VERSION 5.7 ;
BUSBITCHARS "[]" ;
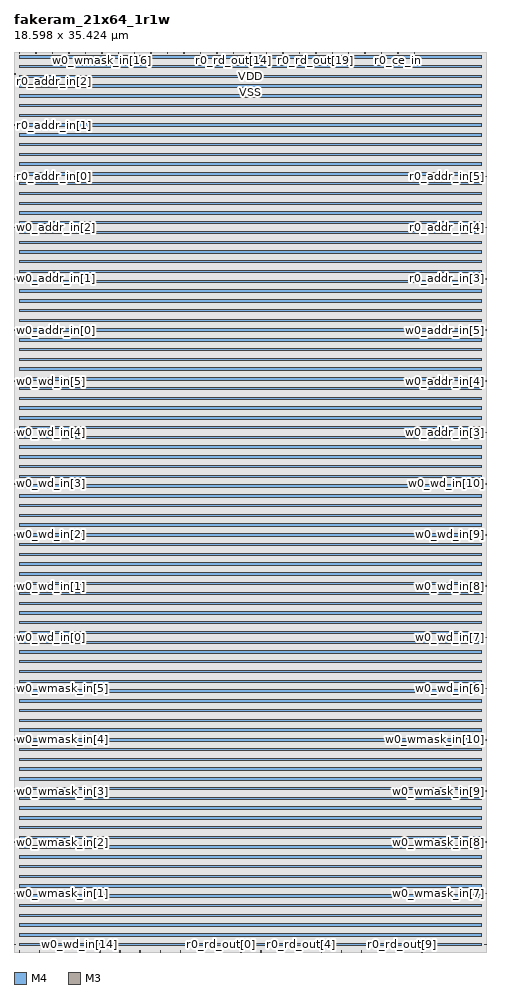
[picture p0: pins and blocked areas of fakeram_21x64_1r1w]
MACRO fakeram_21x64_1r1w
  FOREIGN fakeram_21x64_1r1w 0 0 ;
  SYMMETRY X Y R90 ;
  SIZE 18.598 BY 35.424 ;
  CLASS BLOCK ;
  PIN w0_wmask_in[0]
    DIRECTION INPUT ;
    USE SIGNAL ;
    SHAPE ABUTMENT ;
    PORT
      LAYER M4 ;
      RECT 0.000 0.276 0.072 0.300 ;
    END
  END w0_wmask_in[0]
  PIN w0_wmask_in[1]
    DIRECTION INPUT ;
    USE SIGNAL ;
    SHAPE ABUTMENT ;
    PORT
      LAYER M4 ;
      RECT 0.000 2.292 0.072 2.316 ;
    END
  END w0_wmask_in[1]
  PIN w0_wmask_in[2]
    DIRECTION INPUT ;
    USE SIGNAL ;
    SHAPE ABUTMENT ;
    PORT
      LAYER M4 ;
      RECT 0.000 4.308 0.072 4.332 ;
    END
  END w0_wmask_in[2]
  PIN w0_wmask_in[3]
    DIRECTION INPUT ;
    USE SIGNAL ;
    SHAPE ABUTMENT ;
    PORT
      LAYER M4 ;
      RECT 0.000 6.324 0.072 6.348 ;
    END
  END w0_wmask_in[3]
  PIN w0_wmask_in[4]
    DIRECTION INPUT ;
    USE SIGNAL ;
    SHAPE ABUTMENT ;
    PORT
      LAYER M4 ;
      RECT 0.000 8.340 0.072 8.364 ;
    END
  END w0_wmask_in[4]
  PIN w0_wmask_in[5]
    DIRECTION INPUT ;
    USE SIGNAL ;
    SHAPE ABUTMENT ;
    PORT
      LAYER M4 ;
      RECT 0.000 10.356 0.072 10.380 ;
    END
  END w0_wmask_in[5]
  PIN w0_wmask_in[6]
    DIRECTION INPUT ;
    USE SIGNAL ;
    SHAPE ABUTMENT ;
    PORT
      LAYER M4 ;
      RECT 18.526 0.276 18.598 0.300 ;
    END
  END w0_wmask_in[6]
  PIN w0_wmask_in[7]
    DIRECTION INPUT ;
    USE SIGNAL ;
    SHAPE ABUTMENT ;
    PORT
      LAYER M4 ;
      RECT 18.526 2.292 18.598 2.316 ;
    END
  END w0_wmask_in[7]
  PIN w0_wmask_in[8]
    DIRECTION INPUT ;
    USE SIGNAL ;
    SHAPE ABUTMENT ;
    PORT
      LAYER M4 ;
      RECT 18.526 4.308 18.598 4.332 ;
    END
  END w0_wmask_in[8]
  PIN w0_wmask_in[9]
    DIRECTION INPUT ;
    USE SIGNAL ;
    SHAPE ABUTMENT ;
    PORT
      LAYER M4 ;
      RECT 18.526 6.324 18.598 6.348 ;
    END
  END w0_wmask_in[9]
  PIN w0_wmask_in[10]
    DIRECTION INPUT ;
    USE SIGNAL ;
    SHAPE ABUTMENT ;
    PORT
      LAYER M4 ;
      RECT 18.526 8.340 18.598 8.364 ;
    END
  END w0_wmask_in[10]
  PIN w0_wmask_in[11]
    DIRECTION INPUT ;
    USE SIGNAL ;
    SHAPE ABUTMENT ;
    PORT
      LAYER M3 ;
      RECT 0.207 35.370 0.225 35.424 ;
    END
  END w0_wmask_in[11]
  PIN w0_wmask_in[12]
    DIRECTION INPUT ;
    USE SIGNAL ;
    SHAPE ABUTMENT ;
    PORT
      LAYER M3 ;
      RECT 0.855 35.370 0.873 35.424 ;
    END
  END w0_wmask_in[12]
  PIN w0_wmask_in[13]
    DIRECTION INPUT ;
    USE SIGNAL ;
    SHAPE ABUTMENT ;
    PORT
      LAYER M3 ;
      RECT 1.503 35.370 1.521 35.424 ;
    END
  END w0_wmask_in[13]
  PIN w0_wmask_in[14]
    DIRECTION INPUT ;
    USE SIGNAL ;
    SHAPE ABUTMENT ;
    PORT
      LAYER M3 ;
      RECT 2.151 35.370 2.169 35.424 ;
    END
  END w0_wmask_in[14]
  PIN w0_wmask_in[15]
    DIRECTION INPUT ;
    USE SIGNAL ;
    SHAPE ABUTMENT ;
    PORT
      LAYER M3 ;
      RECT 2.799 35.370 2.817 35.424 ;
    END
  END w0_wmask_in[15]
  PIN w0_wmask_in[16]
    DIRECTION INPUT ;
    USE SIGNAL ;
    SHAPE ABUTMENT ;
    PORT
      LAYER M3 ;
      RECT 3.447 35.370 3.465 35.424 ;
    END
  END w0_wmask_in[16]
  PIN w0_wmask_in[17]
    DIRECTION INPUT ;
    USE SIGNAL ;
    SHAPE ABUTMENT ;
    PORT
      LAYER M3 ;
      RECT 4.095 35.370 4.113 35.424 ;
    END
  END w0_wmask_in[17]
  PIN w0_wmask_in[18]
    DIRECTION INPUT ;
    USE SIGNAL ;
    SHAPE ABUTMENT ;
    PORT
      LAYER M3 ;
      RECT 4.743 35.370 4.761 35.424 ;
    END
  END w0_wmask_in[18]
  PIN w0_wmask_in[19]
    DIRECTION INPUT ;
    USE SIGNAL ;
    SHAPE ABUTMENT ;
    PORT
      LAYER M3 ;
      RECT 5.391 35.370 5.409 35.424 ;
    END
  END w0_wmask_in[19]
  PIN w0_wmask_in[20]
    DIRECTION INPUT ;
    USE SIGNAL ;
    SHAPE ABUTMENT ;
    PORT
      LAYER M3 ;
      RECT 6.039 35.370 6.057 35.424 ;
    END
  END w0_wmask_in[20]
  PIN w0_wd_in[0]
    DIRECTION INPUT ;
    USE SIGNAL ;
    SHAPE ABUTMENT ;
    PORT
      LAYER M4 ;
      RECT 0.000 12.372 0.072 12.396 ;
    END
  END w0_wd_in[0]
  PIN w0_wd_in[1]
    DIRECTION INPUT ;
    USE SIGNAL ;
    SHAPE ABUTMENT ;
    PORT
      LAYER M4 ;
      RECT 0.000 14.388 0.072 14.412 ;
    END
  END w0_wd_in[1]
  PIN w0_wd_in[2]
    DIRECTION INPUT ;
    USE SIGNAL ;
    SHAPE ABUTMENT ;
    PORT
      LAYER M4 ;
      RECT 0.000 16.404 0.072 16.428 ;
    END
  END w0_wd_in[2]
  PIN w0_wd_in[3]
    DIRECTION INPUT ;
    USE SIGNAL ;
    SHAPE ABUTMENT ;
    PORT
      LAYER M4 ;
      RECT 0.000 18.420 0.072 18.444 ;
    END
  END w0_wd_in[3]
  PIN w0_wd_in[4]
    DIRECTION INPUT ;
    USE SIGNAL ;
    SHAPE ABUTMENT ;
    PORT
      LAYER M4 ;
      RECT 0.000 20.436 0.072 20.460 ;
    END
  END w0_wd_in[4]
  PIN w0_wd_in[5]
    DIRECTION INPUT ;
    USE SIGNAL ;
    SHAPE ABUTMENT ;
    PORT
      LAYER M4 ;
      RECT 0.000 22.452 0.072 22.476 ;
    END
  END w0_wd_in[5]
  PIN w0_wd_in[6]
    DIRECTION INPUT ;
    USE SIGNAL ;
    SHAPE ABUTMENT ;
    PORT
      LAYER M4 ;
      RECT 18.526 10.356 18.598 10.380 ;
    END
  END w0_wd_in[6]
  PIN w0_wd_in[7]
    DIRECTION INPUT ;
    USE SIGNAL ;
    SHAPE ABUTMENT ;
    PORT
      LAYER M4 ;
      RECT 18.526 12.372 18.598 12.396 ;
    END
  END w0_wd_in[7]
  PIN w0_wd_in[8]
    DIRECTION INPUT ;
    USE SIGNAL ;
    SHAPE ABUTMENT ;
    PORT
      LAYER M4 ;
      RECT 18.526 14.388 18.598 14.412 ;
    END
  END w0_wd_in[8]
  PIN w0_wd_in[9]
    DIRECTION INPUT ;
    USE SIGNAL ;
    SHAPE ABUTMENT ;
    PORT
      LAYER M4 ;
      RECT 18.526 16.404 18.598 16.428 ;
    END
  END w0_wd_in[9]
  PIN w0_wd_in[10]
    DIRECTION INPUT ;
    USE SIGNAL ;
    SHAPE ABUTMENT ;
    PORT
      LAYER M4 ;
      RECT 18.526 18.420 18.598 18.444 ;
    END
  END w0_wd_in[10]
  PIN w0_wd_in[11]
    DIRECTION INPUT ;
    USE SIGNAL ;
    SHAPE ABUTMENT ;
    PORT
      LAYER M3 ;
      RECT 0.207 0.000 0.225 0.054 ;
    END
  END w0_wd_in[11]
  PIN w0_wd_in[12]
    DIRECTION INPUT ;
    USE SIGNAL ;
    SHAPE ABUTMENT ;
    PORT
      LAYER M3 ;
      RECT 0.999 0.000 1.017 0.054 ;
    END
  END w0_wd_in[12]
  PIN w0_wd_in[13]
    DIRECTION INPUT ;
    USE SIGNAL ;
    SHAPE ABUTMENT ;
    PORT
      LAYER M3 ;
      RECT 1.791 0.000 1.809 0.054 ;
    END
  END w0_wd_in[13]
  PIN w0_wd_in[14]
    DIRECTION INPUT ;
    USE SIGNAL ;
    SHAPE ABUTMENT ;
    PORT
      LAYER M3 ;
      RECT 2.583 0.000 2.601 0.054 ;
    END
  END w0_wd_in[14]
  PIN w0_wd_in[15]
    DIRECTION INPUT ;
    USE SIGNAL ;
    SHAPE ABUTMENT ;
    PORT
      LAYER M3 ;
      RECT 3.375 0.000 3.393 0.054 ;
    END
  END w0_wd_in[15]
  PIN w0_wd_in[16]
    DIRECTION INPUT ;
    USE SIGNAL ;
    SHAPE ABUTMENT ;
    PORT
      LAYER M3 ;
      RECT 4.167 0.000 4.185 0.054 ;
    END
  END w0_wd_in[16]
  PIN w0_wd_in[17]
    DIRECTION INPUT ;
    USE SIGNAL ;
    SHAPE ABUTMENT ;
    PORT
      LAYER M3 ;
      RECT 4.959 0.000 4.977 0.054 ;
    END
  END w0_wd_in[17]
  PIN w0_wd_in[18]
    DIRECTION INPUT ;
    USE SIGNAL ;
    SHAPE ABUTMENT ;
    PORT
      LAYER M3 ;
      RECT 5.751 0.000 5.769 0.054 ;
    END
  END w0_wd_in[18]
  PIN w0_wd_in[19]
    DIRECTION INPUT ;
    USE SIGNAL ;
    SHAPE ABUTMENT ;
    PORT
      LAYER M3 ;
      RECT 6.543 0.000 6.561 0.054 ;
    END
  END w0_wd_in[19]
  PIN w0_wd_in[20]
    DIRECTION INPUT ;
    USE SIGNAL ;
    SHAPE ABUTMENT ;
    PORT
      LAYER M3 ;
      RECT 7.335 0.000 7.353 0.054 ;
    END
  END w0_wd_in[20]
  PIN r0_rd_out[0]
    DIRECTION OUTPUT ;
    USE SIGNAL ;
    SHAPE ABUTMENT ;
    PORT
      LAYER M3 ;
      RECT 8.127 0.000 8.145 0.054 ;
    END
  END r0_rd_out[0]
  PIN r0_rd_out[1]
    DIRECTION OUTPUT ;
    USE SIGNAL ;
    SHAPE ABUTMENT ;
    PORT
      LAYER M3 ;
      RECT 8.919 0.000 8.937 0.054 ;
    END
  END r0_rd_out[1]
  PIN r0_rd_out[2]
    DIRECTION OUTPUT ;
    USE SIGNAL ;
    SHAPE ABUTMENT ;
    PORT
      LAYER M3 ;
      RECT 9.711 0.000 9.729 0.054 ;
    END
  END r0_rd_out[2]
  PIN r0_rd_out[3]
    DIRECTION OUTPUT ;
    USE SIGNAL ;
    SHAPE ABUTMENT ;
    PORT
      LAYER M3 ;
      RECT 10.503 0.000 10.521 0.054 ;
    END
  END r0_rd_out[3]
  PIN r0_rd_out[4]
    DIRECTION OUTPUT ;
    USE SIGNAL ;
    SHAPE ABUTMENT ;
    PORT
      LAYER M3 ;
      RECT 11.295 0.000 11.313 0.054 ;
    END
  END r0_rd_out[4]
  PIN r0_rd_out[5]
    DIRECTION OUTPUT ;
    USE SIGNAL ;
    SHAPE ABUTMENT ;
    PORT
      LAYER M3 ;
      RECT 12.087 0.000 12.105 0.054 ;
    END
  END r0_rd_out[5]
  PIN r0_rd_out[6]
    DIRECTION OUTPUT ;
    USE SIGNAL ;
    SHAPE ABUTMENT ;
    PORT
      LAYER M3 ;
      RECT 12.879 0.000 12.897 0.054 ;
    END
  END r0_rd_out[6]
  PIN r0_rd_out[7]
    DIRECTION OUTPUT ;
    USE SIGNAL ;
    SHAPE ABUTMENT ;
    PORT
      LAYER M3 ;
      RECT 13.671 0.000 13.689 0.054 ;
    END
  END r0_rd_out[7]
  PIN r0_rd_out[8]
    DIRECTION OUTPUT ;
    USE SIGNAL ;
    SHAPE ABUTMENT ;
    PORT
      LAYER M3 ;
      RECT 14.463 0.000 14.481 0.054 ;
    END
  END r0_rd_out[8]
  PIN r0_rd_out[9]
    DIRECTION OUTPUT ;
    USE SIGNAL ;
    SHAPE ABUTMENT ;
    PORT
      LAYER M3 ;
      RECT 15.255 0.000 15.273 0.054 ;
    END
  END r0_rd_out[9]
  PIN r0_rd_out[10]
    DIRECTION OUTPUT ;
    USE SIGNAL ;
    SHAPE ABUTMENT ;
    PORT
      LAYER M3 ;
      RECT 16.047 0.000 16.065 0.054 ;
    END
  END r0_rd_out[10]
  PIN r0_rd_out[11]
    DIRECTION OUTPUT ;
    USE SIGNAL ;
    SHAPE ABUTMENT ;
    PORT
      LAYER M3 ;
      RECT 6.687 35.370 6.705 35.424 ;
    END
  END r0_rd_out[11]
  PIN r0_rd_out[12]
    DIRECTION OUTPUT ;
    USE SIGNAL ;
    SHAPE ABUTMENT ;
    PORT
      LAYER M3 ;
      RECT 7.335 35.370 7.353 35.424 ;
    END
  END r0_rd_out[12]
  PIN r0_rd_out[13]
    DIRECTION OUTPUT ;
    USE SIGNAL ;
    SHAPE ABUTMENT ;
    PORT
      LAYER M3 ;
      RECT 7.983 35.370 8.001 35.424 ;
    END
  END r0_rd_out[13]
  PIN r0_rd_out[14]
    DIRECTION OUTPUT ;
    USE SIGNAL ;
    SHAPE ABUTMENT ;
    PORT
      LAYER M3 ;
      RECT 8.631 35.370 8.649 35.424 ;
    END
  END r0_rd_out[14]
  PIN r0_rd_out[15]
    DIRECTION OUTPUT ;
    USE SIGNAL ;
    SHAPE ABUTMENT ;
    PORT
      LAYER M3 ;
      RECT 9.279 35.370 9.297 35.424 ;
    END
  END r0_rd_out[15]
  PIN r0_rd_out[16]
    DIRECTION OUTPUT ;
    USE SIGNAL ;
    SHAPE ABUTMENT ;
    PORT
      LAYER M3 ;
      RECT 9.927 35.370 9.945 35.424 ;
    END
  END r0_rd_out[16]
  PIN r0_rd_out[17]
    DIRECTION OUTPUT ;
    USE SIGNAL ;
    SHAPE ABUTMENT ;
    PORT
      LAYER M3 ;
      RECT 10.575 35.370 10.593 35.424 ;
    END
  END r0_rd_out[17]
  PIN r0_rd_out[18]
    DIRECTION OUTPUT ;
    USE SIGNAL ;
    SHAPE ABUTMENT ;
    PORT
      LAYER M3 ;
      RECT 11.223 35.370 11.241 35.424 ;
    END
  END r0_rd_out[18]
  PIN r0_rd_out[19]
    DIRECTION OUTPUT ;
    USE SIGNAL ;
    SHAPE ABUTMENT ;
    PORT
      LAYER M3 ;
      RECT 11.871 35.370 11.889 35.424 ;
    END
  END r0_rd_out[19]
  PIN r0_rd_out[20]
    DIRECTION OUTPUT ;
    USE SIGNAL ;
    SHAPE ABUTMENT ;
    PORT
      LAYER M3 ;
      RECT 12.519 35.370 12.537 35.424 ;
    END
  END r0_rd_out[20]
  PIN w0_addr_in[0]
    DIRECTION INPUT ;
    USE SIGNAL ;
    SHAPE ABUTMENT ;
    PORT
      LAYER M4 ;
      RECT 0.000 24.468 0.072 24.492 ;
    END
  END w0_addr_in[0]
  PIN w0_addr_in[1]
    DIRECTION INPUT ;
    USE SIGNAL ;
    SHAPE ABUTMENT ;
    PORT
      LAYER M4 ;
      RECT 0.000 26.484 0.072 26.508 ;
    END
  END w0_addr_in[1]
  PIN w0_addr_in[2]
    DIRECTION INPUT ;
    USE SIGNAL ;
    SHAPE ABUTMENT ;
    PORT
      LAYER M4 ;
      RECT 0.000 28.500 0.072 28.524 ;
    END
  END w0_addr_in[2]
  PIN w0_addr_in[3]
    DIRECTION INPUT ;
    USE SIGNAL ;
    SHAPE ABUTMENT ;
    PORT
      LAYER M4 ;
      RECT 18.526 20.436 18.598 20.460 ;
    END
  END w0_addr_in[3]
  PIN w0_addr_in[4]
    DIRECTION INPUT ;
    USE SIGNAL ;
    SHAPE ABUTMENT ;
    PORT
      LAYER M4 ;
      RECT 18.526 22.452 18.598 22.476 ;
    END
  END w0_addr_in[4]
  PIN w0_addr_in[5]
    DIRECTION INPUT ;
    USE SIGNAL ;
    SHAPE ABUTMENT ;
    PORT
      LAYER M4 ;
      RECT 18.526 24.468 18.598 24.492 ;
    END
  END w0_addr_in[5]
  PIN r0_addr_in[0]
    DIRECTION INPUT ;
    USE SIGNAL ;
    SHAPE ABUTMENT ;
    PORT
      LAYER M4 ;
      RECT 0.000 30.516 0.072 30.540 ;
    END
  END r0_addr_in[0]
  PIN r0_addr_in[1]
    DIRECTION INPUT ;
    USE SIGNAL ;
    SHAPE ABUTMENT ;
    PORT
      LAYER M4 ;
      RECT 0.000 32.532 0.072 32.556 ;
    END
  END r0_addr_in[1]
  PIN r0_addr_in[2]
    DIRECTION INPUT ;
    USE SIGNAL ;
    SHAPE ABUTMENT ;
    PORT
      LAYER M4 ;
      RECT 0.000 34.548 0.072 34.572 ;
    END
  END r0_addr_in[2]
  PIN r0_addr_in[3]
    DIRECTION INPUT ;
    USE SIGNAL ;
    SHAPE ABUTMENT ;
    PORT
      LAYER M4 ;
      RECT 18.526 26.484 18.598 26.508 ;
    END
  END r0_addr_in[3]
  PIN r0_addr_in[4]
    DIRECTION INPUT ;
    USE SIGNAL ;
    SHAPE ABUTMENT ;
    PORT
      LAYER M4 ;
      RECT 18.526 28.500 18.598 28.524 ;
    END
  END r0_addr_in[4]
  PIN r0_addr_in[5]
    DIRECTION INPUT ;
    USE SIGNAL ;
    SHAPE ABUTMENT ;
    PORT
      LAYER M4 ;
      RECT 18.526 30.516 18.598 30.540 ;
    END
  END r0_addr_in[5]
  PIN w0_we_in
    DIRECTION INPUT ;
    USE SIGNAL ;
    SHAPE ABUTMENT ;
    PORT
      LAYER M3 ;
      RECT 13.167 35.370 13.185 35.424 ;
    END
  END w0_we_in
  PIN w0_ce_in
    DIRECTION INPUT ;
    USE SIGNAL ;
    SHAPE ABUTMENT ;
    PORT
      LAYER M3 ;
      RECT 13.815 35.370 13.833 35.424 ;
    END
  END w0_ce_in
  PIN w0_clk
    DIRECTION INPUT ;
    USE SIGNAL ;
    SHAPE ABUTMENT ;
    PORT
      LAYER M3 ;
      RECT 14.463 35.370 14.481 35.424 ;
    END
  END w0_clk
  PIN r0_ce_in
    DIRECTION INPUT ;
    USE SIGNAL ;
    SHAPE ABUTMENT ;
    PORT
      LAYER M3 ;
      RECT 15.111 35.370 15.129 35.424 ;
    END
  END r0_ce_in
  PIN r0_clk
    DIRECTION INPUT ;
    USE SIGNAL ;
    SHAPE ABUTMENT ;
    PORT
      LAYER M3 ;
      RECT 15.759 35.370 15.777 35.424 ;
    END
  END r0_clk
  PIN VSS
    DIRECTION INOUT ;
    USE GROUND ;
    PORT
      LAYER M4 ;
      RECT 0.216 0.240 18.382 0.336 ;
      RECT 0.216 1.008 18.382 1.104 ;
      RECT 0.216 1.776 18.382 1.872 ;
      RECT 0.216 2.544 18.382 2.640 ;
      RECT 0.216 3.312 18.382 3.408 ;
      RECT 0.216 4.080 18.382 4.176 ;
      RECT 0.216 4.848 18.382 4.944 ;
      RECT 0.216 5.616 18.382 5.712 ;
      RECT 0.216 6.384 18.382 6.480 ;
      RECT 0.216 7.152 18.382 7.248 ;
      RECT 0.216 7.920 18.382 8.016 ;
      RECT 0.216 8.688 18.382 8.784 ;
      RECT 0.216 9.456 18.382 9.552 ;
      RECT 0.216 10.224 18.382 10.320 ;
      RECT 0.216 10.992 18.382 11.088 ;
      RECT 0.216 11.760 18.382 11.856 ;
      RECT 0.216 12.528 18.382 12.624 ;
      RECT 0.216 13.296 18.382 13.392 ;
      RECT 0.216 14.064 18.382 14.160 ;
      RECT 0.216 14.832 18.382 14.928 ;
      RECT 0.216 15.600 18.382 15.696 ;
      RECT 0.216 16.368 18.382 16.464 ;
      RECT 0.216 17.136 18.382 17.232 ;
      RECT 0.216 17.904 18.382 18.000 ;
      RECT 0.216 18.672 18.382 18.768 ;
      RECT 0.216 19.440 18.382 19.536 ;
      RECT 0.216 20.208 18.382 20.304 ;
      RECT 0.216 20.976 18.382 21.072 ;
      RECT 0.216 21.744 18.382 21.840 ;
      RECT 0.216 22.512 18.382 22.608 ;
      RECT 0.216 23.280 18.382 23.376 ;
      RECT 0.216 24.048 18.382 24.144 ;
      RECT 0.216 24.816 18.382 24.912 ;
      RECT 0.216 25.584 18.382 25.680 ;
      RECT 0.216 26.352 18.382 26.448 ;
      RECT 0.216 27.120 18.382 27.216 ;
      RECT 0.216 27.888 18.382 27.984 ;
      RECT 0.216 28.656 18.382 28.752 ;
      RECT 0.216 29.424 18.382 29.520 ;
      RECT 0.216 30.192 18.382 30.288 ;
      RECT 0.216 30.960 18.382 31.056 ;
      RECT 0.216 31.728 18.382 31.824 ;
      RECT 0.216 32.496 18.382 32.592 ;
      RECT 0.216 33.264 18.382 33.360 ;
      RECT 0.216 34.032 18.382 34.128 ;
      RECT 0.216 34.800 18.382 34.896 ;
    END
  END VSS
  PIN VDD
    DIRECTION INOUT ;
    USE POWER ;
    PORT
      LAYER M4 ;
      RECT 0.216 0.624 18.382 0.720 ;
      RECT 0.216 1.392 18.382 1.488 ;
      RECT 0.216 2.160 18.382 2.256 ;
      RECT 0.216 2.928 18.382 3.024 ;
      RECT 0.216 3.696 18.382 3.792 ;
      RECT 0.216 4.464 18.382 4.560 ;
      RECT 0.216 5.232 18.382 5.328 ;
      RECT 0.216 6.000 18.382 6.096 ;
      RECT 0.216 6.768 18.382 6.864 ;
      RECT 0.216 7.536 18.382 7.632 ;
      RECT 0.216 8.304 18.382 8.400 ;
      RECT 0.216 9.072 18.382 9.168 ;
      RECT 0.216 9.840 18.382 9.936 ;
      RECT 0.216 10.608 18.382 10.704 ;
      RECT 0.216 11.376 18.382 11.472 ;
      RECT 0.216 12.144 18.382 12.240 ;
      RECT 0.216 12.912 18.382 13.008 ;
      RECT 0.216 13.680 18.382 13.776 ;
      RECT 0.216 14.448 18.382 14.544 ;
      RECT 0.216 15.216 18.382 15.312 ;
      RECT 0.216 15.984 18.382 16.080 ;
      RECT 0.216 16.752 18.382 16.848 ;
      RECT 0.216 17.520 18.382 17.616 ;
      RECT 0.216 18.288 18.382 18.384 ;
      RECT 0.216 19.056 18.382 19.152 ;
      RECT 0.216 19.824 18.382 19.920 ;
      RECT 0.216 20.592 18.382 20.688 ;
      RECT 0.216 21.360 18.382 21.456 ;
      RECT 0.216 22.128 18.382 22.224 ;
      RECT 0.216 22.896 18.382 22.992 ;
      RECT 0.216 23.664 18.382 23.760 ;
      RECT 0.216 24.432 18.382 24.528 ;
      RECT 0.216 25.200 18.382 25.296 ;
      RECT 0.216 25.968 18.382 26.064 ;
      RECT 0.216 26.736 18.382 26.832 ;
      RECT 0.216 27.504 18.382 27.600 ;
      RECT 0.216 28.272 18.382 28.368 ;
      RECT 0.216 29.040 18.382 29.136 ;
      RECT 0.216 29.808 18.382 29.904 ;
      RECT 0.216 30.576 18.382 30.672 ;
      RECT 0.216 31.344 18.382 31.440 ;
      RECT 0.216 32.112 18.382 32.208 ;
      RECT 0.216 32.880 18.382 32.976 ;
      RECT 0.216 33.648 18.382 33.744 ;
      RECT 0.216 34.416 18.382 34.512 ;
      RECT 0.216 35.184 18.382 35.280 ;
    END
  END VDD
  OBS
    LAYER M1 ;
    RECT 0 0 18.598 35.424 ;
    LAYER M2 ;
    RECT 0 0 18.598 35.424 ;
    LAYER M3 ;
    RECT 0 0 18.598 35.424 ;
    LAYER M4 ;
    RECT 0 0 18.598 35.424 ;
  END
END fakeram_21x64_1r1w

END LIBRARY
